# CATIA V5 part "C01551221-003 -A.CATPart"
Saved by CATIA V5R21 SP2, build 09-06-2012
Part number: C01551221-003
Revision: ---
Description: PROPRIETARY NOTICE (do not delete / modify)  ***************************************************************************************************  LA SOCIETE EN COMMANDITE  AIRBUS CANADA  ("AIRBUS CANADA")  PAR  L'INTERMEDIAIRE  DE  SES  DIVISIONS  ET/OU  FILIALES  CORPORATIVES,  FOURNIT  LES PRESENTES  INFORMATIONS  AU  GOUVERNEMENT  A  TITRE CONFIDENTIEL. CES  INFORMATIONS ONT UNE TENEUR CONFIDENTIELLE,  AVEC DROITS DE PROPRIETE,  ET NOUS LES CONSIDERONS  EXCLUS  DE   L'APPLICATION  DE  LA LOI SUR L'ACCES A L'INFORMATION  (CANADA),  LES  LOIS  SUR  L'ACCES  A  L'INFORMATION  EUROPEENNES,  LE FREEDOM OF INFORMATION ACT (ETATS-UNIS) ET D'AUTRES LOIS SEMBLABLES. ELLES  PEUVENT  AUSSI  CONSTITUER DES SECRETS INDUSTRIELS DE NOTRE SOCIETE OU DE TIERCES PARTIES. LA DIVULGATION  PUBLIQUE  DE CES  INFORMATIONS NUIRAIT A AIRBUS CANADA OU A DES TIERCES PARTIES.  CES INFORMATIONS PEUVENT EGALEMENT CONTENIR  DES DONNEES QUI SONT CONTROLEE PAR DES LOIS DE CONTROLE DES EXPORTATIONS DU CANADA, L’EUROPE OU LES  ETATS-  UNIS. TOUTE EXPORTATION OU REEXPORTATION DE DONNEES CONTROLEES SANS AUTORISATION EST STRICTEMENT INTERDITE.  TOUTE INTENTION DE LES DIVULGUER EN TOUT OU EN PARTIE DEVRA ETRE SIGNIFIEE A L'AVANCE ET PAR ECRIT AU VICE-  PRESIDENT, SERVICES JURIDIQUES ET CONFORMITE ET SECRETAIRE CORPORATIF D'AIRBUS CANADA.    AIRBUS CANADA LIMITED PARTNERSHIP  ("AIRBUS CANADA"),  BY ITS AFFILIATES AND/OR SUBSIDIARIES, PROVIDES THIS  INFORMATION TO THE GOVERNMENT IN CONFIDENCE. THIS IS PROPRIETARY CONFIDENTIAL INFORMATION WHICH WE CONSIDER  EXCLUDED  FROM  THE  APPLICATION OF THE ACCESS TO INFORMATION ACT (CANADA),  THE FREEDOM OF INFORMATION ACT  (U.S.A.),  THE ACCESS TO INFORMATION LAWS IN EUROPE, AND OTHER SIMILAR LEGISLATION. AND MAY ALSO CONSTITUTE  TRADE SECRETS OF OUR  COMPANY OR THIRD PARTIES.  PUBLIC  RELEASE  OF  THIS INFORMATION  WOULD BE HARMFUL TO  AIRBUS CANADA OR THIRD PARTIES.  THIS  INFORMATION  MAY  ALSO  CONTAIN DATA THAT IS CONTROLLED BY CANADIAN,  EUROPEAN, OR U.S.A. EXPORT CONTROL LAWS. ANY UNAUTHORIZED EXPORT OR RE-EXPORT OF ANY EXPORT CONTROLLED DATA  IS STRICTLY PROHIBITED  ANY INTENTION TO DISCLOSE SUCH INFORMATION,  OR  PART THEREOF,  MUST BE NOTIFIED IN  ADVANCE AND IN WRITING TO THE VICE PRESIDENT, LEGAL AND COMPLIANCE AND CORPORATE SECRETARY OF AIRBUS CANADA.        LES RENSEIGNEMENTS,  LES DONNEES  ET  DESSINS  TECHNIQUES  DIVULGUES  DANS  LES PRESENTES SONT LA PROPRIETE  EXCLUSIVE DE LA SOCIETE EN COMMANDITE AIRBUS CANADA ("AIRBUS CANADA") OU COMPORTENT DES DROITS DE PROPRIETE  APPARTENANT  A  AUTRUI ET NE PEUVENT ETRE DIVULGUES  A  QUICONQUE  NI  UTILISES PAR QUI QUE CE SOIT SANS LE  CONSENTEMENT  ECRIT  D’AIRBUS  CANADA.  LE DETENTEUR DES  PRESENTES  S'ENGAGE, DANS TOUTES CIRCONSTANCES, A  GARDER CONFIDENTIELS LES DONNEES ET DESSINS TECHNIQUES QU'ELLES CONTIENNENT.   CE QUI PRECEDE NE S'APPLIQUE  PAS  AUX PERSONNES  QUI  ONT DES DROITS DE PROPRIETE SUR CES RENSEIGNEMENTS,  DONNEES TECHNIQUES ET DESSINS  DANS LA MESURE OU CES DROITS EXISTENT.    THE INFORMATION,  TECHNICAL DATA  AND  DESIGNS DISCLOSED HEREIN ARE THE EXCLUSIVE PROPERTY OF AIRBUS CANADA  LIMITED PARTNERSHIP  ("AIRBUS CANADA")  OR  CONTAIN PROPRIETARY RIGHTS OF OTHERS  AND ARE NOT TO BE USED OR  DISCLOSED  TO  OTHERS WITHOUT THE WRITTEN CONSENT OF AIRBUS CANADA.  THE RECIPIENT OF THIS DOCUMENT, BY ITS  RETENTION  AND  USE  AGREES TO  HOLD  IN  CONFIDENCE  THE  TECHNICAL DATA AND DESIGNS CONTAINED HEREIN. THE  FOREGOING SHALL NOT APPLY TO PERSONS HAVING PROPRIETARY RIGHTS TO SUCH INFORMATION,  TECHNICAL DATA OR SUCH  DESIGNS TO THE EXTENT THAT SUCH RIGHTS EXIST.    Copyright 2020 Airbus Canada Limited Partnership. All Rights Reserved.  ***********************************
Property "Title": "FITTING, GUIDE ROLLER"
Property "Dataset Type": "DETAIL"
Property "Supplier Name And CAGE Code": "AIRBUS CANADA LIMITED PARTNERSHIP L0J48"
Property "Major Supplier Code": "LP"
Property "3D Only": "N/A"
Property "Material Form": "BAR - SQUARE"
Property "Finish Code": "T001"
Property "PCCN": "2"
Property "Organization": "DESIGN"
Property "Design Authority Program": "BD-500"
Property "Color Coded": "N/A"
Property "Thickness": 3
Property "Inside Diameter": 0
Property "Outside Diameter": 0
Property "Length": 0
Property "Width": 0
Property "Wall": 0
Property "Wire Gauge": "-"
Property "Alloy": "6AL-4V"
Property "Final Condition": "ANL"
Property "Density": "N/A"
Property "Form": "N/A"
Property "Grade/Composition": "N/A"
Property "Material Class": "N/A"
Property "Mesh Cell Size": "N/A"
Property "Standard Spec Die": "N/A"
Property "Type": "N/A"
Property "Style": "N/A"
Property "MFG Process": "MACHINED"
Property "Material Specification Production": "AMS4928"
Property "Material Description Production": "TITANIUM"
Property "Dimensions": "DIMENSIONS ARE IN INCHES"
Property "Roughness": "ALL MACHINED SURFACES 125 Ra MAX"
Property "Eng. Tolerances": "LINEAR .XX= +/-.03; .XXX= +/-.010; ANGULAR= +/-0.5 DEG"
Property "Tool Design Tolerances": "LINEAR .X= +/-.06; .XX= +/-.015; .XXX= +/-.005; .XXXX= +/-.001; ANGULAR= +/-0.5 DEG"
Property "REFERENCE": "C01551221-001 --"
Property "AU_CLASS": "PSLIASSE"
Property "Project": "BA"
Publications: "PartBody", "Extract.1_Datum_A", "Extract.1_Datum_B", "Extract.1_Datum_C", "Extract.1_Datum_D1", "Extract.1_Datum_E"
Material "TI-6AL-4V": density 4428.78 kg/m3, Young's modulus 1.11695e+11 Pa, Poisson ratio 0.31
Bounding box of the stored display mesh (mm): x 17.252 to 183.527, y -29.609 to 29.609, z -34.925 to 22.851
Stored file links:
  C:\Users\CQQZ006\Desktop\A220钢钛件\舱门\C01551221-003\C01551221-003 -A.CATPart

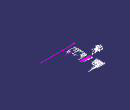
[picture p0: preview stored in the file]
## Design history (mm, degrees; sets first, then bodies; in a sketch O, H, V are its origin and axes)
Parameters
  `BUSHING LENGTH` = 5.842 mm
  `DISTANCE 1` = 27.94 mm
Part_3D_Annotations1 "CATTPSSet"
AxisSystem1 "Absolute Axis System": origin (0, 0, 0), X (1, 0, 0), Y (0, 1, 0), Z (0, 0, 1)
Sketch1 "Sketch.1" on Line1, origin (58.3049, 0.0001, 0.0001), H (1, 0, 0), V (0, 1, 0)
  point P1 (-11.684, 14.2653)
  point P2 (-11.684, 14.2653)
  line L1 (-11.684, 14.2653) -> (-11.684, 40.64)
  line L2 (-11.684, 40.64) -> (-8.636, 40.64)
  line L3 (-8.636, 40.64) -> (-8.636, 14.2653)
  line L4 (-8.636, 14.2653) -> (10.16, 14.2653)
  point P6 (10.16, 14.2653)
  line L5 (13.535, 13.97) -> (52.9273, 13.97)
  point P8 (52.9273, 13.97)
  line L6 (57.4455, 13.335) -> (78.3273, 13.335)
  line L7 (113.284, 12.7) -> (113.284, 14.0335)
  line L8 (113.284, 14.0335) -> (115.824, 14.0335)
  line L9 (115.824, 14.0335) -> (115.824, 12.681)
  line L10 (115.824, 12.681) -> (125.222, 12.681)
  line L11 (125.222, 0) -> (125.222, 12.681)
  point P13 (125.222, 0)
  reference projected line E1 (-41.0528, -127) -> (-41.0528, 127) from edge of Project4
  reference projected line E2 (119.38, -127) -> (119.38, 127) from edge of Project5
  reference intersected line E3 through (0, 0) direction (1, 0) from Plane3
  reference intersected line E4 through (0, 0) direction (0, 1) from Plane1
  line L12 (10.16, 14.2653) -> (13.535, 13.97)
  line L13 (52.9273, 13.97) -> (57.4455, 13.335)
  line L14 (-40.0826, 16.51) -> (-36.9888, 16.51)
  line L15 (-36.9888, 16.51) -> (-36.9888, 10.16)
  line L16 (-36.9888, 10.16) -> (-27.0051, 10.16)
  line L17 (-27.0051, 10.16) -> (-11.684, 14.2653)
  point P27 (-41.0528, 0)
  line L18 (-41.0528, 0) -> (-41.0528, 13.97)
  arc A1 centre (-37.2428, 13.97) radius 3.81 from (-41.0528, 13.97) to (-40.0826, 16.51) cw
  line L19 (78.3273, 13.335) -> (82.8455, 12.7)
  line L20 (82.8455, 12.7) -> (113.284, 12.7)
  point P31 (78.3273, 13.335)
  distance L1 L3 = 3.048
  distance L2 E3 = 40.64
  distance L5 E3 = 13.97
  distance L9 L7 = 2.54
  distance L10 E3 = 12.681
  distance L8 E3 = 14.0335
  distance E4 L3 = 8.636
  distance L9 E2 = 3.556
  distance L11 E2 = 5.842 {= `BUSHING LENGTH`}
  distance E4 E2 = 119.38 (reference)
  distance P6 E4 = 10.16
  angle L12 L4 = 5
  angle L13 L5 = 8
  distance L4 E3 = 14.2653
  distance L14 E3 = 16.51
  distance L15 E1 = 4.064
  distance L16 E3 = 10.16
  angle L17 L1 = 105
  length L18 = 13.97
  radius A1 = 3.81
  distance L6 E3 = 13.335
  distance P8 E1 = 93.98
  distance L20 E3 = 12.7
  distance P31 E1 = 119.38
  angle L19 L6 = 8
  coincidence: P1 P2, P1 L4, P13 E3, P27 E3, L18 E1
  tangency: A1 L18
Shaft1: profile Sketch1, axis Line1, angle 360
Set1
  Plane1 "EDGE_FR_FWD": linked copy from another document
  Plane2 "FWD ROLLER INTERCOSTAL_LWR": linked copy from another document
  Line1 "LWR ROLLER AXIS": linked copy from another document
  Plane3 "LWR ROLLER STIFFENER": linked copy from another document
  DatumSurface1 "INNER SURF INTERCOSTALS": linked copy from another document
Set2 "Pilot_Holes"
  Set3 "Pilot_Holes_5/32"
    Set4 "Hole_Construction"
      Plane4: type Offset, RefPlane Plane1, Offset 10.16, reversed
      Sketch2 on Line5, origin (58.3049, 0.0001, 0.0001), H (0, -1, 0), V (0, 0, 1)
        reference projected line E1 (-127, 0) -> (127, 0) from Line5
        point P3 (0, 0)
        construction line L1 (0, 0) -> (21.997, 12.7)
        point P4 (21.997, 12.7)
        point P5 (21.997, 12.7)
        point P6 (0, -27.305)
        point P7 (-21.997, 12.7)
        construction circle A1 centre (0, 0) radius 25.4
        reference intersected line E2 through (0, 0) direction (0, 1) from Plane3
        construction line L2 (-21.997, 12.7) -> (0, 0)
        construction circle A2 centre (21.997, 12.7) radius 5.842
        construction circle A3 centre (-21.997, 12.7) radius 5.842
        radius A1 = 25.4
        radius A2 = 5.842
        radius A3 = 5.842
        angle L2 E2 = 60
        angle L1 E2 = 60
        distance E1 P6 = 27.305
        coincidence: P5 P4, A1 P4, P3 E2, P3 E1, P7 A1, P6 E2
    Project1: ToProject Sketch2.P6, Support Plane4
    Project2: ToProject Sketch2.P7, Support Plane4
    Project3: ToProject Sketch2.P5, Support Plane4
    Line2 "Fstnr_Axis.1": type Normal, RefPoint Project1, RefSkin Plane4, Start -6.35, End 6.35
    Line3 "Fstnr_Axis.2": type Normal, RefPoint Project3, RefSkin Plane4, Start -6.35, End 6.35
    Line4 "Fstnr_Axis.3": type Normal, RefPoint Project2, RefSkin Plane4, Start -6.35, End 6.35
Set5 "Geometrical Set for 3D Annotations"
  Set6 "No Show Geometry"
    Extract1 "Extract.1_Datum_A": ExtractElem face of Shaft1 from Sketch1.L4
    Extract2 "Extract.1_Datum_B": ExtractElem face of Shaft1 from Sketch1.L10
    Extract3 "Extract.1_Datum_C": ExtractElem face of Shaft1 from Sketch1.L3
    Extract4 "Extract.1_Datum_D1": ExtractElem vertex of Point2
    Extract5 "Extract.1_Datum_E": ExtractElem face of Groove1 from Sketch4.L10
    Plane5: stored without definition
    Point1: type OnCurve, Support edge [face of Shaft1 from Sketch1.L1 | face of Pocket1 from Sketch5.A8], RefPoint vertex [face of Pocket1 from Sketch5.A6 | face of Shaft1 from Sketch1.L1 | face of Pocket1 from Sketch5.A8], Length -2.54
  Set7 "VIEW.3_GS"
    Point2: type OnSurface, Support face of Pocket1 from Sketch5.A8, RefPoint Point1, Length 1.778, Direction edge [face of Pocket1 from Sketch5.A6 | face of Pocket1 from Sketch5.A8]
Set8 "Construction_Geometry"
  Set9 "Master Geom Construction"
    Intersect1: ToIntersect1 Plane1, ToIntersect2 Plane3
    Intersect2: ToIntersect1 Intersect1, ToIntersect2 Line1
    Line5: type Angle, RefPoint Intersect2, Curve Intersect1, Support Plane1, Start -127, End 127, Angle 90
  Set10 "Fwd Surface Geom"
    Plane6 "FWD_PLANE": type Offset, RefPlane Plane1, Offset 41.0528, reversed
    Project4 "FWD_SURFACE_project": ToProject Line5, Support Plane6
    Project5 "FWR_ROLLER_INTERCOSTAL_project": ToProject Line5, Support Plane2
  Set11 "Machined Surface"
    Offset1: Offset DatumSurface1, Length 6.604 {= .14in+.12in}
  Set12 "Pin Holes"
    Sketch3 on zx-plane, origin (0, 0, 0), H (-1, 0, 0), V (0, 0, 1)
      point P1 (-54.8441, 6.3501)
      reference projected line E1 through (0, 0.0001) direction (-1, 0) from axis of face of Shaft1 from Sketch1.L5
      reference intersected line E2 through (-17.2521, 0) direction (0, -1) from Plane6
      distance P1 E1 = 6.35
      distance P1 E2 = 37.592
    Line6: type Normal, RefPoint Sketch3, RefSkin zx-plane, Start 1.27, End 7.62
    Plane7: type Angle, RefPlane Plane3, Direction Line1, Angle 30
    Plane8: type Offset, RefPlane face of Shaft1 from Sketch1.L3, Offset 109.22, reversed
    Intersect3: ToIntersect1 Plane8, ToIntersect2 {inverselocal InverseElem Plane7}
Body1 (main body)
  Body2 "Body.1"
    Sketch4 "Sketch.2" on Line1, origin (58.3049, 0.0001, 0.0001), H (1, 0, 0), V (0, 1, 0)
      line L1 (125.222, 11.176) -> (35.1473, 11.176)
      line L2 (35.1473, 11.176) -> (35.1473, 10.16)
      line L3 (35.1473, 10.16) -> (22.8283, 10.16)
      line L4 (-41.0528, 6.3716) -> (-41.0528, 0)
      line L5 (-41.0528, 0) -> (125.222, 0)
      point P7 (125.222, 0)
      line L6 (125.222, 0) -> (125.222, 11.176)
      reference projected line E1 (-41.0528, -127) -> (-41.0528, 127) from edge of Project4
      reference projected line E2 (119.38, -127) -> (119.38, 127) from edge of Project5
      point P13 (125.222, 0)
      reference intersected line E3 through (0, 0) direction (1, 0) from Plane3
      reference intersected line E4 through (0, 0) direction (0, 1) from Plane1
      line L7 (22.8283, 3.3592) -> (22.8283, 10.16)
      line L8 (17.7483, 7.9375) -> (17.7483, 3.3592)
      line L9 (17.7483, 3.3592) -> (22.8283, 3.3592)
      line L10 (-41.0528, 6.3716) -> (5.0483, 6.3716)
      line L11 (5.0483, 7.9375) -> (17.7483, 7.9375)
      line L12 (5.0483, 6.3716) -> (5.0483, 7.9375)
      distance L6 E2 = 5.842 {= `BUSHING LENGTH`}
      distance E2 E4 = 119.38 (reference)
      distance L1 L5 = 11.176
      distance L5 L3 = 10.16
      distance L9 L5 = 3.3592
      distance L10 L5 = 6.3716
      distance L8 L12 = 12.7
      distance L11 L5 = 7.9375
      distance E1 L8 = 58.801
      distance E1 L7 = 63.881
      distance E1 L2 = 76.2
      coincidence: L4 E1, P7 P13, L5 E3
      horizontal: L11 H
      vertical: L12 V
    Groove1: profile Sketch4, axis Sketch4.H, angle 360
    Fillet1: radius 1.27, on edge [face of Groove1 from Sketch4.L2 | face of Groove1 from Sketch4.L1]; edge [face of Groove1 from Sketch4.L7 | face of Groove1 from Sketch4.L3]; edge [face of Groove1 from Sketch4.L11 | face of Groove1 from Sketch4.L8]; edge [face of Groove1 from Sketch4.L12 | face of Groove1 from Sketch4.L11]
  Assemble1 "Assemble.1": tool Body2
  Body3 "Body.2"
    Sketch5 "Sketch.3" on Line5, origin (58.3049, 0.0001, 0.0001), H (0, -1, 0), V (0, 0, 1)
      point P1 (-6.0148, -31.9833)
      point P2 (0, -36.3804)
      line L1 (-44.45, 48.26) -> (44.45, 48.26)
      line L2 (44.45, 48.26) -> (44.45, -48.26)
      line L3 (44.45, -48.26) -> (-44.45, -48.26)
      line L4 (-44.45, -48.26) -> (-44.45, 48.26)
      arc A1 centre (-21.997, 12.7) radius 7.62 from (-23.7337, 20.1195) to (-29.1696, 10.1272) ccw
      point P7 (-21.997, 12.7)
      point P8 (-23.7337, 20.1195)
      point P9 (-29.1696, 10.1272)
      construction line L5 (0, 0) -> (-21.997, 12.7)
      point P10 (0, 22.86)
      construction line L6 (27.9608, 22.86) -> (-23.9725, 22.86)
      reference intersected line E1 through (0, 31.4938) direction (0, 1) from Plane3
      construction circle A2 centre (0, 0) radius 25.4
      arc A3 centre (0, -27.305) radius 7.62 from (-6.0148, -31.9833) to (6.0148, -31.9833) ccw
      point P15 (0, -27.305)
      point P16 (6.0148, -31.9833)
      arc A4 centre (114.2809, 61.5833) radius 152.4 from (-29.1696, 10.1272) to (-6.0148, -31.9833) ccw
      point P18 (-6.0148, -31.9833)
      point P19 (6.0148, -31.9833)
      point P20 (29.1696, 10.1272)
      arc A5 centre (-114.2809, 61.5833) radius 152.4 from (29.1696, 10.1272) to (6.0148, -31.9833) cw
      point P22 (23.7337, 20.1195)
      arc A6 centre (21.997, 12.7) radius 7.62 from (23.7337, 20.1195) to (29.1696, 10.1272) cw
      construction circle A7 centre (-21.997, 12.7) radius 5.842
      arc A8 centre (0, -81.28) radius 104.14 from (23.7337, 20.1195) to (-23.7337, 20.1195) ccw
      point P26 (0, -81.28)
      construction circle A9 centre (0, 0) radius 27.305
      length L1 = 88.9
      length L4 = 96.52
      distance V L4 = 44.45 {= Sketch5.length(L1) /2}
      distance H L3 = 48.26 {= Sketch5.length(L4) /2}
      radius A1 = 7.62
      distance H L6 = 22.86
      radius A2 = 25.4
      radius A3 = 7.62
      radius A4 = 152.4
      radius A7 = 5.842
      angle L5 E1 = 60
      radius A9 = 27.305
      horizontal: L1 H, L3 H
      vertical: L2 V, L4 V
      coincidence: P10 V, P10 L6, P7 A2, P18 P1, P26 E1, P15 E1, P16 P19, A9 P15
      tangency: A3 A4, A4 A1, A8 A6, A8 A1, A8 L6
      symmetry: P18 P19 E1, P9 P20 E1, A4 A5 E1, P8 P22 E1, A1 A6 E1
    Pocket1: profile Sketch5, direction (1, 0, 0), length 50.8, opposite side length 304.8
  Assemble2 "Assemble.2": tool Body3
  Chamfer1: length 0.508, angle 45, on edge [face of Shaft1 from Sketch1.L10 | face of Shaft1 from Sketch1.L11]; edge [face of Groove1 from Sketch4.L10 | face of Shaft1 from Sketch1.L18]
  Chamfer2: length 0.889, angle 45, on edge [face of Groove1 from Sketch4.L9 | face of Groove1 from Sketch4.L8]
  Fillet2: radius 0.762, on edge [face of Shaft1 from Sketch1.L9 | face of Shaft1 from Sketch1.L10]; edge [face of Shaft1 from Sketch1.L20 | face of Shaft1 from Sketch1.L7]
  Fillet3: radius 4.064, on edge [face of Shaft1 from Sketch1.L17 | face of Shaft1 from Sketch1.L1]
  Fillet4: radius 4.064, on edge [face of Shaft1 from Sketch1.L15 | face of Shaft1 from Sketch1.L16]; edge [face of Shaft1 from Sketch1.L16 | face of Shaft1 from Sketch1.L17]
  Fillet5: radius 10.16, on edge [face of Shaft1 from Sketch1.L12 | face of Shaft1 from Sketch1.L5]; edge [face of Shaft1 from Sketch1.L13 | face of Shaft1 from Sketch1.L6]; edge [face of Shaft1 from Sketch1.L19 | face of Shaft1 from Sketch1.L20]
  Sketch6 on {plane type Normal, Curve Line6, RefPoint vertex of Line6}, origin (54.7491, 1.27, -19.5104), H (1, 0, 0), V (0, 0, -1)
    point P1 (0.0951, -25.8605)
    reference projected point E1 (0.0951, -25.8605) from Line6
    coincidence: P1 E1
  Hole1: placed by Sketch6, at (54.8441, 1.27, 6.3501) direction (0, 1, 0), diameter 2.4257, through (limit type 6)
  Sketch7 on {plane type Tangent, Support face of Shaft1 from Sketch1.L6, RefPoint {point type OnSurface, Support face of Shaft1 from Sketch1.L6, RefPoint {point stored without definition}, Length 0, Direction (0, -866.0254, 500)}}, origin (187.8451, 14.435, -6.991), H (1, 0, 0), V (0, 0.8625, 0.5061)
    point P1 (-28.9562, -9.0057)
    intersected point E1 (-28.9562, -9.0057) from Intersect3
    coincidence: E1 P1
  Hole2: placed by Sketch7, at (158.8889, 6.6677, -11.5487) direction (0, 0.5, -0.866), diameter 6.35, through (limit type 6)
  Fillet6: radius 2.286, on edge [face of Shaft1 from Sketch1.L3 | face of Shaft1 from Sketch1.L4]
  Sketch8 on face of Shaft1 from Sketch1.L3, origin (49.6689, 0.0001, -27.3049), H (0, 1, 0), V (0, 0, 1)
    point P1 (0, 0)
    intersected point E1 (0, 0) from Line2
    coincidence: E1 P1
  Hole3: placed by Sketch8, at (49.6689, 0.0001, -27.3049) direction (-1, 0, 0), diameter 2.4, through (limit type 6)
  Sketch9 on face of Shaft1 from Sketch1.L3, origin (49.6689, -21.997, 12.7001), H (0, 1, 0), V (0, 0, 1)
    point P1 (0, 0)
    intersected point E1 (0, 0) from Line3
    coincidence: E1 P1
  Hole4: placed by Sketch9, at (49.6689, -21.997, 12.7001) direction (-1, 0, 0), diameter 2.1, through (limit type 6)
  Sketch10 on face of Shaft1 from Sketch1.L3, origin (49.6689, 21.9971, 12.7001), H (0, 1, 0), V (0, 0, 1)
    point P1 (0, 0)
    intersected point E1 (0, 0) from Line4
    coincidence: E1 P1
  Hole5: placed by Sketch10, at (49.6689, 21.9971, 12.7001) direction (-1, 0, 0), diameter 2.1, through (limit type 6)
